VERSION 5.7 ;
  NOWIREEXTENSIONATPIN ON ;
  DIVIDERCHAR "/" ;
  BUSBITCHARS "[]" ;
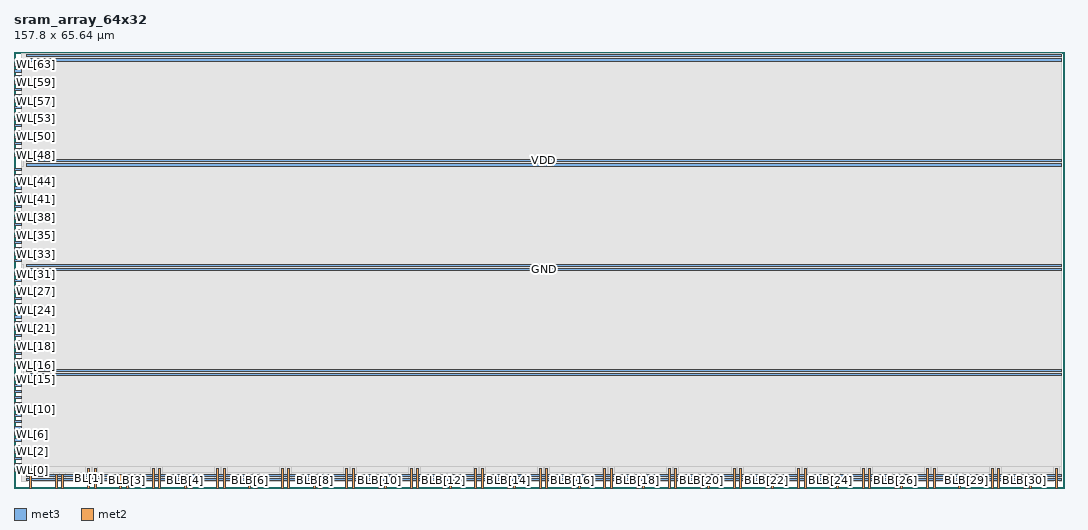
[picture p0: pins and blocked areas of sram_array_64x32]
MACRO sram_array_64x32
  CLASS BLOCK ;
  FOREIGN sram_array_64x32 ;
  ORIGIN 0.000 0.000 ;
  SIZE 157.800 BY 65.640 ;
  PIN WL[0]
    DIRECTION INPUT ;
    USE SIGNAL ;
    ANTENNAGATEAREA 4.032000 ;
    PORT
      LAYER met3 ;
        RECT 0.000 2.490 1.160 2.820 ;
    END
  END WL[0]
  PIN WL[1]
    DIRECTION INPUT ;
    USE SIGNAL ;
    ANTENNAGATEAREA 4.032000 ;
    PORT
      LAYER met3 ;
        RECT 0.000 3.400 1.160 3.730 ;
    END
  END WL[1]
  PIN WL[2]
    DIRECTION INPUT ;
    USE SIGNAL ;
    ANTENNAGATEAREA 4.032000 ;
    PORT
      LAYER met3 ;
        RECT 0.000 4.310 1.160 4.640 ;
    END
  END WL[2]
  PIN WL[3]
    DIRECTION INPUT ;
    USE SIGNAL ;
    ANTENNAGATEAREA 4.032000 ;
    PORT
      LAYER met3 ;
        RECT 0.000 5.220 1.160 5.550 ;
    END
  END WL[3]
  PIN WL[4]
    DIRECTION INPUT ;
    USE SIGNAL ;
    ANTENNAGATEAREA 4.032000 ;
    PORT
      LAYER met3 ;
        RECT 0.000 6.130 1.160 6.460 ;
    END
  END WL[4]
  PIN WL[5]
    DIRECTION INPUT ;
    USE SIGNAL ;
    ANTENNAGATEAREA 4.032000 ;
    PORT
      LAYER met3 ;
        RECT 0.000 7.040 1.160 7.370 ;
    END
  END WL[5]
  PIN WL[6]
    DIRECTION INPUT ;
    USE SIGNAL ;
    ANTENNAGATEAREA 4.032000 ;
    PORT
      LAYER met3 ;
        RECT 0.000 7.950 1.160 8.280 ;
    END
  END WL[6]
  PIN WL[7]
    DIRECTION INPUT ;
    USE SIGNAL ;
    ANTENNAGATEAREA 4.032000 ;
    PORT
      LAYER met3 ;
        RECT 0.000 8.860 1.160 9.190 ;
    END
  END WL[7]
  PIN WL[8]
    DIRECTION INPUT ;
    USE SIGNAL ;
    ANTENNAGATEAREA 4.032000 ;
    PORT
      LAYER met3 ;
        RECT 0.000 9.770 1.160 10.100 ;
    END
  END WL[8]
  PIN WL[9]
    DIRECTION INPUT ;
    USE SIGNAL ;
    ANTENNAGATEAREA 4.032000 ;
    PORT
      LAYER met3 ;
        RECT 0.000 10.680 1.160 11.010 ;
    END
  END WL[9]
  PIN WL[10]
    DIRECTION INPUT ;
    USE SIGNAL ;
    ANTENNAGATEAREA 4.032000 ;
    PORT
      LAYER met3 ;
        RECT 0.000 11.590 1.160 11.920 ;
    END
  END WL[10]
  PIN WL[11]
    DIRECTION INPUT ;
    USE SIGNAL ;
    ANTENNAGATEAREA 4.032000 ;
    PORT
      LAYER met3 ;
        RECT 0.000 12.500 1.160 12.830 ;
    END
  END WL[11]
  PIN WL[12]
    DIRECTION INPUT ;
    USE SIGNAL ;
    ANTENNAGATEAREA 4.032000 ;
    PORT
      LAYER met3 ;
        RECT 0.000 13.410 1.160 13.740 ;
    END
  END WL[12]
  PIN WL[13]
    DIRECTION INPUT ;
    USE SIGNAL ;
    ANTENNAGATEAREA 4.032000 ;
    PORT
      LAYER met3 ;
        RECT 0.000 14.320 1.160 14.650 ;
    END
  END WL[13]
  PIN WL[14]
    DIRECTION INPUT ;
    USE SIGNAL ;
    ANTENNAGATEAREA 4.032000 ;
    PORT
      LAYER met3 ;
        RECT 0.000 15.230 1.160 15.560 ;
    END
  END WL[14]
  PIN WL[15]
    DIRECTION INPUT ;
    USE SIGNAL ;
    ANTENNAGATEAREA 4.032000 ;
    PORT
      LAYER met3 ;
        RECT 0.000 16.140 1.160 16.470 ;
    END
  END WL[15]
  PIN WL[16]
    DIRECTION INPUT ;
    USE SIGNAL ;
    ANTENNAGATEAREA 4.032000 ;
    PORT
      LAYER met3 ;
        RECT 0.000 18.250 1.160 18.580 ;
    END
  END WL[16]
  PIN WL[17]
    DIRECTION INPUT ;
    USE SIGNAL ;
    ANTENNAGATEAREA 4.032000 ;
    PORT
      LAYER met3 ;
        RECT 0.000 19.160 1.160 19.490 ;
    END
  END WL[17]
  PIN WL[18]
    DIRECTION INPUT ;
    USE SIGNAL ;
    ANTENNAGATEAREA 4.032000 ;
    PORT
      LAYER met3 ;
        RECT 0.000 20.070 1.160 20.400 ;
    END
  END WL[18]
  PIN WL[19]
    DIRECTION INPUT ;
    USE SIGNAL ;
    ANTENNAGATEAREA 4.032000 ;
    PORT
      LAYER met3 ;
        RECT 0.000 20.980 1.160 21.310 ;
    END
  END WL[19]
  PIN WL[20]
    DIRECTION INPUT ;
    USE SIGNAL ;
    ANTENNAGATEAREA 4.032000 ;
    PORT
      LAYER met3 ;
        RECT 0.000 21.890 1.160 22.220 ;
    END
  END WL[20]
  PIN WL[21]
    DIRECTION INPUT ;
    USE SIGNAL ;
    ANTENNAGATEAREA 4.032000 ;
    PORT
      LAYER met3 ;
        RECT 0.000 22.800 1.160 23.130 ;
    END
  END WL[21]
  PIN WL[22]
    DIRECTION INPUT ;
    USE SIGNAL ;
    ANTENNAGATEAREA 4.032000 ;
    PORT
      LAYER met3 ;
        RECT 0.000 23.710 1.160 24.040 ;
    END
  END WL[22]
  PIN WL[23]
    DIRECTION INPUT ;
    USE SIGNAL ;
    ANTENNAGATEAREA 4.032000 ;
    PORT
      LAYER met3 ;
        RECT 0.000 24.620 1.160 24.950 ;
    END
  END WL[23]
  PIN WL[24]
    DIRECTION INPUT ;
    USE SIGNAL ;
    ANTENNAGATEAREA 4.032000 ;
    PORT
      LAYER met3 ;
        RECT 0.000 25.530 1.160 25.860 ;
    END
  END WL[24]
  PIN WL[25]
    DIRECTION INPUT ;
    USE SIGNAL ;
    ANTENNAGATEAREA 4.032000 ;
    PORT
      LAYER met3 ;
        RECT 0.000 26.440 1.160 26.770 ;
    END
  END WL[25]
  PIN WL[26]
    DIRECTION INPUT ;
    USE SIGNAL ;
    ANTENNAGATEAREA 4.032000 ;
    PORT
      LAYER met3 ;
        RECT 0.000 27.350 1.160 27.680 ;
    END
  END WL[26]
  PIN WL[27]
    DIRECTION INPUT ;
    USE SIGNAL ;
    ANTENNAGATEAREA 4.032000 ;
    PORT
      LAYER met3 ;
        RECT 0.000 28.260 1.160 28.590 ;
    END
  END WL[27]
  PIN WL[28]
    DIRECTION INPUT ;
    USE SIGNAL ;
    ANTENNAGATEAREA 4.032000 ;
    PORT
      LAYER met3 ;
        RECT 0.000 29.170 1.160 29.500 ;
    END
  END WL[28]
  PIN WL[29]
    DIRECTION INPUT ;
    USE SIGNAL ;
    ANTENNAGATEAREA 4.032000 ;
    PORT
      LAYER met3 ;
        RECT 0.000 30.080 1.160 30.410 ;
    END
  END WL[29]
  PIN WL[30]
    DIRECTION INPUT ;
    USE SIGNAL ;
    ANTENNAGATEAREA 4.032000 ;
    PORT
      LAYER met3 ;
        RECT 0.000 30.990 1.160 31.320 ;
    END
  END WL[30]
  PIN WL[31]
    DIRECTION INPUT ;
    USE SIGNAL ;
    ANTENNAGATEAREA 4.032000 ;
    PORT
      LAYER met3 ;
        RECT 0.000 31.900 1.160 32.230 ;
    END
  END WL[31]
  PIN WL[32]
    DIRECTION INPUT ;
    USE SIGNAL ;
    ANTENNAGATEAREA 4.032000 ;
    PORT
      LAYER met3 ;
        RECT 0.000 34.010 1.160 34.340 ;
    END
  END WL[32]
  PIN WL[33]
    DIRECTION INPUT ;
    USE SIGNAL ;
    ANTENNAGATEAREA 4.032000 ;
    PORT
      LAYER met3 ;
        RECT 0.000 34.920 1.160 35.250 ;
    END
  END WL[33]
  PIN WL[34]
    DIRECTION INPUT ;
    USE SIGNAL ;
    ANTENNAGATEAREA 4.032000 ;
    PORT
      LAYER met3 ;
        RECT 0.000 35.830 1.160 36.160 ;
    END
  END WL[34]
  PIN WL[35]
    DIRECTION INPUT ;
    USE SIGNAL ;
    ANTENNAGATEAREA 4.032000 ;
    PORT
      LAYER met3 ;
        RECT 0.000 36.740 1.160 37.070 ;
    END
  END WL[35]
  PIN WL[36]
    DIRECTION INPUT ;
    USE SIGNAL ;
    ANTENNAGATEAREA 4.032000 ;
    PORT
      LAYER met3 ;
        RECT 0.000 37.650 1.160 37.980 ;
    END
  END WL[36]
  PIN WL[37]
    DIRECTION INPUT ;
    USE SIGNAL ;
    ANTENNAGATEAREA 4.032000 ;
    PORT
      LAYER met3 ;
        RECT 0.000 38.560 1.160 38.890 ;
    END
  END WL[37]
  PIN WL[38]
    DIRECTION INPUT ;
    USE SIGNAL ;
    ANTENNAGATEAREA 4.032000 ;
    PORT
      LAYER met3 ;
        RECT 0.000 39.470 1.160 39.800 ;
    END
  END WL[38]
  PIN WL[39]
    DIRECTION INPUT ;
    USE SIGNAL ;
    ANTENNAGATEAREA 4.032000 ;
    PORT
      LAYER met3 ;
        RECT 0.000 40.380 1.160 40.710 ;
    END
  END WL[39]
  PIN WL[40]
    DIRECTION INPUT ;
    USE SIGNAL ;
    ANTENNAGATEAREA 4.032000 ;
    PORT
      LAYER met3 ;
        RECT 0.000 41.290 1.160 41.620 ;
    END
  END WL[40]
  PIN WL[41]
    DIRECTION INPUT ;
    USE SIGNAL ;
    ANTENNAGATEAREA 4.032000 ;
    PORT
      LAYER met3 ;
        RECT 0.000 42.200 1.160 42.530 ;
    END
  END WL[41]
  PIN WL[42]
    DIRECTION INPUT ;
    USE SIGNAL ;
    ANTENNAGATEAREA 4.032000 ;
    PORT
      LAYER met3 ;
        RECT 0.000 43.110 1.160 43.440 ;
    END
  END WL[42]
  PIN WL[43]
    DIRECTION INPUT ;
    USE SIGNAL ;
    ANTENNAGATEAREA 4.032000 ;
    PORT
      LAYER met3 ;
        RECT 0.000 44.020 1.160 44.350 ;
    END
  END WL[43]
  PIN WL[44]
    DIRECTION INPUT ;
    USE SIGNAL ;
    ANTENNAGATEAREA 4.032000 ;
    PORT
      LAYER met3 ;
        RECT 0.000 44.930 1.160 45.260 ;
    END
  END WL[44]
  PIN WL[45]
    DIRECTION INPUT ;
    USE SIGNAL ;
    ANTENNAGATEAREA 4.032000 ;
    PORT
      LAYER met3 ;
        RECT 0.000 45.840 1.160 46.170 ;
    END
  END WL[45]
  PIN WL[46]
    DIRECTION INPUT ;
    USE SIGNAL ;
    ANTENNAGATEAREA 4.032000 ;
    PORT
      LAYER met3 ;
        RECT 0.000 46.750 1.160 47.080 ;
    END
  END WL[46]
  PIN WL[47]
    DIRECTION INPUT ;
    USE SIGNAL ;
    ANTENNAGATEAREA 4.032000 ;
    PORT
      LAYER met3 ;
        RECT 0.000 47.660 1.160 47.990 ;
    END
  END WL[47]
  PIN WL[48]
    DIRECTION INPUT ;
    USE SIGNAL ;
    ANTENNAGATEAREA 4.032000 ;
    PORT
      LAYER met3 ;
        RECT 0.000 49.770 1.160 50.100 ;
    END
  END WL[48]
  PIN WL[49]
    DIRECTION INPUT ;
    USE SIGNAL ;
    ANTENNAGATEAREA 4.032000 ;
    PORT
      LAYER met3 ;
        RECT 0.000 50.680 1.160 51.010 ;
    END
  END WL[49]
  PIN WL[50]
    DIRECTION INPUT ;
    USE SIGNAL ;
    ANTENNAGATEAREA 4.032000 ;
    PORT
      LAYER met3 ;
        RECT 0.000 51.590 1.160 51.920 ;
    END
  END WL[50]
  PIN WL[51]
    DIRECTION INPUT ;
    USE SIGNAL ;
    ANTENNAGATEAREA 4.032000 ;
    PORT
      LAYER met3 ;
        RECT 0.000 52.500 1.160 52.830 ;
    END
  END WL[51]
  PIN WL[52]
    DIRECTION INPUT ;
    USE SIGNAL ;
    ANTENNAGATEAREA 4.032000 ;
    PORT
      LAYER met3 ;
        RECT 0.000 53.410 1.160 53.740 ;
    END
  END WL[52]
  PIN WL[53]
    DIRECTION INPUT ;
    USE SIGNAL ;
    ANTENNAGATEAREA 4.032000 ;
    PORT
      LAYER met3 ;
        RECT 0.000 54.320 1.160 54.650 ;
    END
  END WL[53]
  PIN WL[54]
    DIRECTION INPUT ;
    USE SIGNAL ;
    ANTENNAGATEAREA 4.032000 ;
    PORT
      LAYER met3 ;
        RECT 0.000 55.230 1.160 55.560 ;
    END
  END WL[54]
  PIN WL[55]
    DIRECTION INPUT ;
    USE SIGNAL ;
    ANTENNAGATEAREA 4.032000 ;
    PORT
      LAYER met3 ;
        RECT 0.000 56.140 1.160 56.470 ;
    END
  END WL[55]
  PIN WL[56]
    DIRECTION INPUT ;
    USE SIGNAL ;
    ANTENNAGATEAREA 4.032000 ;
    PORT
      LAYER met3 ;
        RECT 0.000 57.050 1.160 57.380 ;
    END
  END WL[56]
  PIN WL[57]
    DIRECTION INPUT ;
    USE SIGNAL ;
    ANTENNAGATEAREA 4.032000 ;
    PORT
      LAYER met3 ;
        RECT 0.000 57.960 1.160 58.290 ;
    END
  END WL[57]
  PIN WL[58]
    DIRECTION INPUT ;
    USE SIGNAL ;
    ANTENNAGATEAREA 4.032000 ;
    PORT
      LAYER met3 ;
        RECT 0.000 58.870 1.160 59.200 ;
    END
  END WL[58]
  PIN WL[59]
    DIRECTION INPUT ;
    USE SIGNAL ;
    ANTENNAGATEAREA 4.032000 ;
    PORT
      LAYER met3 ;
        RECT 0.000 59.780 1.160 60.110 ;
    END
  END WL[59]
  PIN WL[60]
    DIRECTION INPUT ;
    USE SIGNAL ;
    ANTENNAGATEAREA 4.032000 ;
    PORT
      LAYER met3 ;
        RECT 0.000 60.690 1.160 61.020 ;
    END
  END WL[60]
  PIN WL[61]
    DIRECTION INPUT ;
    USE SIGNAL ;
    ANTENNAGATEAREA 4.032000 ;
    PORT
      LAYER met3 ;
        RECT 0.000 61.600 1.160 61.930 ;
    END
  END WL[61]
  PIN WL[62]
    DIRECTION INPUT ;
    USE SIGNAL ;
    ANTENNAGATEAREA 4.032000 ;
    PORT
      LAYER met3 ;
        RECT 0.000 62.510 1.160 62.840 ;
    END
  END WL[62]
  PIN WL[63]
    DIRECTION INPUT ;
    USE SIGNAL ;
    ANTENNAGATEAREA 4.032000 ;
    PORT
      LAYER met3 ;
        RECT 0.000 63.420 1.160 63.750 ;
    END
  END WL[63]
  PIN BL[0]
    DIRECTION INOUT ;
    USE SIGNAL ;
    ANTENNADIFFAREA 3.763200 ;
    PORT
      LAYER met2 ;
        RECT 2.335 0.000 2.635 2.980 ;
    END
  END BL[0]
  PIN BLB[0]
    DIRECTION INOUT ;
    USE SIGNAL ;
    ANTENNADIFFAREA 4.233600 ;
    PORT
      LAYER met2 ;
        RECT 6.215 0.000 6.515 2.070 ;
    END
  END BLB[0]
  PIN BL[1]
    DIRECTION INOUT ;
    USE SIGNAL ;
    ANTENNADIFFAREA 3.763200 ;
    PORT
      LAYER met2 ;
        RECT 11.065 0.000 11.365 2.980 ;
    END
  END BL[1]
  PIN BLB[1]
    DIRECTION INOUT ;
    USE SIGNAL ;
    ANTENNADIFFAREA 4.233600 ;
    PORT
      LAYER met2 ;
        RECT 7.185 0.000 7.485 2.070 ;
    END
  END BLB[1]
  PIN BL[2]
    DIRECTION INOUT ;
    USE SIGNAL ;
    ANTENNADIFFAREA 3.763200 ;
    PORT
      LAYER met2 ;
        RECT 12.035 0.000 12.335 2.980 ;
    END
  END BL[2]
  PIN BLB[2]
    DIRECTION INOUT ;
    USE SIGNAL ;
    ANTENNADIFFAREA 4.233600 ;
    PORT
      LAYER met2 ;
        RECT 15.915 0.000 16.215 2.070 ;
    END
  END BLB[2]
  PIN BL[3]
    DIRECTION INOUT ;
    USE SIGNAL ;
    ANTENNADIFFAREA 3.763200 ;
    PORT
      LAYER met2 ;
        RECT 20.765 0.000 21.065 2.980 ;
    END
  END BL[3]
  PIN BLB[3]
    DIRECTION INOUT ;
    USE SIGNAL ;
    ANTENNADIFFAREA 4.233600 ;
    PORT
      LAYER met2 ;
        RECT 16.885 0.000 17.185 2.070 ;
    END
  END BLB[3]
  PIN BL[4]
    DIRECTION INOUT ;
    USE SIGNAL ;
    ANTENNADIFFAREA 3.763200 ;
    PORT
      LAYER met2 ;
        RECT 21.735 0.000 22.035 2.980 ;
    END
  END BL[4]
  PIN BLB[4]
    DIRECTION INOUT ;
    USE SIGNAL ;
    ANTENNADIFFAREA 4.233600 ;
    PORT
      LAYER met2 ;
        RECT 25.615 0.000 25.915 2.070 ;
    END
  END BLB[4]
  PIN BL[5]
    DIRECTION INOUT ;
    USE SIGNAL ;
    ANTENNADIFFAREA 3.763200 ;
    PORT
      LAYER met2 ;
        RECT 30.465 0.000 30.765 2.980 ;
    END
  END BL[5]
  PIN BLB[5]
    DIRECTION INOUT ;
    USE SIGNAL ;
    ANTENNADIFFAREA 4.233600 ;
    PORT
      LAYER met2 ;
        RECT 26.585 0.000 26.885 2.070 ;
    END
  END BLB[5]
  PIN BL[6]
    DIRECTION INOUT ;
    USE SIGNAL ;
    ANTENNADIFFAREA 3.763200 ;
    PORT
      LAYER met2 ;
        RECT 31.435 0.000 31.735 2.980 ;
    END
  END BL[6]
  PIN BLB[6]
    DIRECTION INOUT ;
    USE SIGNAL ;
    ANTENNADIFFAREA 4.233600 ;
    PORT
      LAYER met2 ;
        RECT 35.315 0.000 35.615 2.070 ;
    END
  END BLB[6]
  PIN BL[7]
    DIRECTION INOUT ;
    USE SIGNAL ;
    ANTENNADIFFAREA 3.763200 ;
    PORT
      LAYER met2 ;
        RECT 40.165 0.000 40.465 2.980 ;
    END
  END BL[7]
  PIN BLB[7]
    DIRECTION INOUT ;
    USE SIGNAL ;
    ANTENNADIFFAREA 4.233600 ;
    PORT
      LAYER met2 ;
        RECT 36.285 0.000 36.585 2.070 ;
    END
  END BLB[7]
  PIN BL[8]
    DIRECTION INOUT ;
    USE SIGNAL ;
    ANTENNADIFFAREA 3.763200 ;
    PORT
      LAYER met2 ;
        RECT 41.135 0.000 41.435 2.980 ;
    END
  END BL[8]
  PIN BLB[8]
    DIRECTION INOUT ;
    USE SIGNAL ;
    ANTENNADIFFAREA 4.233600 ;
    PORT
      LAYER met2 ;
        RECT 45.015 0.000 45.315 2.070 ;
    END
  END BLB[8]
  PIN BL[9]
    DIRECTION INOUT ;
    USE SIGNAL ;
    ANTENNADIFFAREA 3.763200 ;
    PORT
      LAYER met2 ;
        RECT 49.865 0.000 50.165 2.980 ;
    END
  END BL[9]
  PIN BLB[9]
    DIRECTION INOUT ;
    USE SIGNAL ;
    ANTENNADIFFAREA 4.233600 ;
    PORT
      LAYER met2 ;
        RECT 45.985 0.000 46.285 2.070 ;
    END
  END BLB[9]
  PIN BL[10]
    DIRECTION INOUT ;
    USE SIGNAL ;
    ANTENNADIFFAREA 3.763200 ;
    PORT
      LAYER met2 ;
        RECT 50.835 0.000 51.135 2.980 ;
    END
  END BL[10]
  PIN BLB[10]
    DIRECTION INOUT ;
    USE SIGNAL ;
    ANTENNADIFFAREA 4.233600 ;
    PORT
      LAYER met2 ;
        RECT 54.715 0.000 55.015 2.070 ;
    END
  END BLB[10]
  PIN BL[11]
    DIRECTION INOUT ;
    USE SIGNAL ;
    ANTENNADIFFAREA 3.763200 ;
    PORT
      LAYER met2 ;
        RECT 59.565 0.000 59.865 2.980 ;
    END
  END BL[11]
  PIN BLB[11]
    DIRECTION INOUT ;
    USE SIGNAL ;
    ANTENNADIFFAREA 4.233600 ;
    PORT
      LAYER met2 ;
        RECT 55.685 0.000 55.985 2.070 ;
    END
  END BLB[11]
  PIN BL[12]
    DIRECTION INOUT ;
    USE SIGNAL ;
    ANTENNADIFFAREA 3.763200 ;
    PORT
      LAYER met2 ;
        RECT 60.535 0.000 60.835 2.980 ;
    END
  END BL[12]
  PIN BLB[12]
    DIRECTION INOUT ;
    USE SIGNAL ;
    ANTENNADIFFAREA 4.233600 ;
    PORT
      LAYER met2 ;
        RECT 64.415 0.000 64.715 2.070 ;
    END
  END BLB[12]
  PIN BL[13]
    DIRECTION INOUT ;
    USE SIGNAL ;
    ANTENNADIFFAREA 3.763200 ;
    PORT
      LAYER met2 ;
        RECT 69.265 0.000 69.565 2.980 ;
    END
  END BL[13]
  PIN BLB[13]
    DIRECTION INOUT ;
    USE SIGNAL ;
    ANTENNADIFFAREA 4.233600 ;
    PORT
      LAYER met2 ;
        RECT 65.385 0.000 65.685 2.070 ;
    END
  END BLB[13]
  PIN BL[14]
    DIRECTION INOUT ;
    USE SIGNAL ;
    ANTENNADIFFAREA 3.763200 ;
    PORT
      LAYER met2 ;
        RECT 70.235 0.000 70.535 2.980 ;
    END
  END BL[14]
  PIN BLB[14]
    DIRECTION INOUT ;
    USE SIGNAL ;
    ANTENNADIFFAREA 4.233600 ;
    PORT
      LAYER met2 ;
        RECT 74.115 0.000 74.415 2.070 ;
    END
  END BLB[14]
  PIN BL[15]
    DIRECTION INOUT ;
    USE SIGNAL ;
    ANTENNADIFFAREA 3.763200 ;
    PORT
      LAYER met2 ;
        RECT 78.965 0.000 79.265 2.980 ;
    END
  END BL[15]
  PIN BLB[15]
    DIRECTION INOUT ;
    USE SIGNAL ;
    ANTENNADIFFAREA 4.233600 ;
    PORT
      LAYER met2 ;
        RECT 75.085 0.000 75.385 2.070 ;
    END
  END BLB[15]
  PIN BL[16]
    DIRECTION INOUT ;
    USE SIGNAL ;
    ANTENNADIFFAREA 3.763200 ;
    PORT
      LAYER met2 ;
        RECT 79.935 0.000 80.235 2.980 ;
    END
  END BL[16]
  PIN BLB[16]
    DIRECTION INOUT ;
    USE SIGNAL ;
    ANTENNADIFFAREA 4.233600 ;
    PORT
      LAYER met2 ;
        RECT 83.815 0.000 84.115 2.070 ;
    END
  END BLB[16]
  PIN BL[17]
    DIRECTION INOUT ;
    USE SIGNAL ;
    ANTENNADIFFAREA 3.763200 ;
    PORT
      LAYER met2 ;
        RECT 88.665 0.000 88.965 2.980 ;
    END
  END BL[17]
  PIN BLB[17]
    DIRECTION INOUT ;
    USE SIGNAL ;
    ANTENNADIFFAREA 4.233600 ;
    PORT
      LAYER met2 ;
        RECT 84.785 0.000 85.085 2.070 ;
    END
  END BLB[17]
  PIN BL[18]
    DIRECTION INOUT ;
    USE SIGNAL ;
    ANTENNADIFFAREA 3.763200 ;
    PORT
      LAYER met2 ;
        RECT 89.635 0.000 89.935 2.980 ;
    END
  END BL[18]
  PIN BLB[18]
    DIRECTION INOUT ;
    USE SIGNAL ;
    ANTENNADIFFAREA 4.233600 ;
    PORT
      LAYER met2 ;
        RECT 93.515 0.000 93.815 2.070 ;
    END
  END BLB[18]
  PIN BL[19]
    DIRECTION INOUT ;
    USE SIGNAL ;
    ANTENNADIFFAREA 3.763200 ;
    PORT
      LAYER met2 ;
        RECT 98.365 0.000 98.665 2.980 ;
    END
  END BL[19]
  PIN BLB[19]
    DIRECTION INOUT ;
    USE SIGNAL ;
    ANTENNADIFFAREA 4.233600 ;
    PORT
      LAYER met2 ;
        RECT 94.485 0.000 94.785 2.070 ;
    END
  END BLB[19]
  PIN BL[20]
    DIRECTION INOUT ;
    USE SIGNAL ;
    ANTENNADIFFAREA 3.763200 ;
    PORT
      LAYER met2 ;
        RECT 99.335 0.000 99.635 2.980 ;
    END
  END BL[20]
  PIN BLB[20]
    DIRECTION INOUT ;
    USE SIGNAL ;
    ANTENNADIFFAREA 4.233600 ;
    PORT
      LAYER met2 ;
        RECT 103.215 0.000 103.515 2.070 ;
    END
  END BLB[20]
  PIN BL[21]
    DIRECTION INOUT ;
    USE SIGNAL ;
    ANTENNADIFFAREA 3.763200 ;
    PORT
      LAYER met2 ;
        RECT 108.065 0.000 108.365 2.980 ;
    END
  END BL[21]
  PIN BLB[21]
    DIRECTION INOUT ;
    USE SIGNAL ;
    ANTENNADIFFAREA 4.233600 ;
    PORT
      LAYER met2 ;
        RECT 104.185 0.000 104.485 2.070 ;
    END
  END BLB[21]
  PIN BL[22]
    DIRECTION INOUT ;
    USE SIGNAL ;
    ANTENNADIFFAREA 3.763200 ;
    PORT
      LAYER met2 ;
        RECT 109.035 0.000 109.335 2.980 ;
    END
  END BL[22]
  PIN BLB[22]
    DIRECTION INOUT ;
    USE SIGNAL ;
    ANTENNADIFFAREA 4.233600 ;
    PORT
      LAYER met2 ;
        RECT 112.915 0.000 113.215 2.070 ;
    END
  END BLB[22]
  PIN BL[23]
    DIRECTION INOUT ;
    USE SIGNAL ;
    ANTENNADIFFAREA 3.763200 ;
    PORT
      LAYER met2 ;
        RECT 117.765 0.000 118.065 2.980 ;
    END
  END BL[23]
  PIN BLB[23]
    DIRECTION INOUT ;
    USE SIGNAL ;
    ANTENNADIFFAREA 4.233600 ;
    PORT
      LAYER met2 ;
        RECT 113.885 0.000 114.185 2.070 ;
    END
  END BLB[23]
  PIN BL[24]
    DIRECTION INOUT ;
    USE SIGNAL ;
    ANTENNADIFFAREA 3.763200 ;
    PORT
      LAYER met2 ;
        RECT 118.735 0.000 119.035 2.980 ;
    END
  END BL[24]
  PIN BLB[24]
    DIRECTION INOUT ;
    USE SIGNAL ;
    ANTENNADIFFAREA 4.233600 ;
    PORT
      LAYER met2 ;
        RECT 122.615 0.000 122.915 2.070 ;
    END
  END BLB[24]
  PIN BL[25]
    DIRECTION INOUT ;
    USE SIGNAL ;
    ANTENNADIFFAREA 3.763200 ;
    PORT
      LAYER met2 ;
        RECT 127.465 0.000 127.765 2.980 ;
    END
  END BL[25]
  PIN BLB[25]
    DIRECTION INOUT ;
    USE SIGNAL ;
    ANTENNADIFFAREA 4.233600 ;
    PORT
      LAYER met2 ;
        RECT 123.585 0.000 123.885 2.070 ;
    END
  END BLB[25]
  PIN BL[26]
    DIRECTION INOUT ;
    USE SIGNAL ;
    ANTENNADIFFAREA 3.763200 ;
    PORT
      LAYER met2 ;
        RECT 128.435 0.000 128.735 2.980 ;
    END
  END BL[26]
  PIN BLB[26]
    DIRECTION INOUT ;
    USE SIGNAL ;
    ANTENNADIFFAREA 4.233600 ;
    PORT
      LAYER met2 ;
        RECT 132.315 0.000 132.615 2.070 ;
    END
  END BLB[26]
  PIN BL[27]
    DIRECTION INOUT ;
    USE SIGNAL ;
    ANTENNADIFFAREA 3.763200 ;
    PORT
      LAYER met2 ;
        RECT 137.165 0.000 137.465 2.980 ;
    END
  END BL[27]
  PIN BLB[27]
    DIRECTION INOUT ;
    USE SIGNAL ;
    ANTENNADIFFAREA 4.233600 ;
    PORT
      LAYER met2 ;
        RECT 133.285 0.000 133.585 2.070 ;
    END
  END BLB[27]
  PIN BL[28]
    DIRECTION INOUT ;
    USE SIGNAL ;
    ANTENNADIFFAREA 3.763200 ;
    PORT
      LAYER met2 ;
        RECT 138.135 0.000 138.435 2.980 ;
    END
  END BL[28]
  PIN BLB[28]
    DIRECTION INOUT ;
    USE SIGNAL ;
    ANTENNADIFFAREA 4.233600 ;
    PORT
      LAYER met2 ;
        RECT 142.015 0.000 142.315 2.070 ;
    END
  END BLB[28]
  PIN BL[29]
    DIRECTION INOUT ;
    USE SIGNAL ;
    ANTENNADIFFAREA 3.763200 ;
    PORT
      LAYER met2 ;
        RECT 146.865 0.000 147.165 2.980 ;
    END
  END BL[29]
  PIN BLB[29]
    DIRECTION INOUT ;
    USE SIGNAL ;
    ANTENNADIFFAREA 4.233600 ;
    PORT
      LAYER met2 ;
        RECT 142.985 0.000 143.285 2.070 ;
    END
  END BLB[29]
  PIN BL[30]
    DIRECTION INOUT ;
    USE SIGNAL ;
    ANTENNADIFFAREA 3.763200 ;
    PORT
      LAYER met2 ;
        RECT 147.835 0.000 148.135 2.980 ;
    END
  END BL[30]
  PIN BLB[30]
    DIRECTION INOUT ;
    USE SIGNAL ;
    ANTENNADIFFAREA 4.233600 ;
    PORT
      LAYER met2 ;
        RECT 151.715 0.000 152.015 2.070 ;
    END
  END BLB[30]
  PIN BL[31]
    DIRECTION INOUT ;
    USE SIGNAL ;
    ANTENNADIFFAREA 3.763200 ;
    PORT
      LAYER met2 ;
        RECT 156.565 0.000 156.865 2.980 ;
    END
  END BL[31]
  PIN BLB[31]
    DIRECTION INOUT ;
    USE SIGNAL ;
    ANTENNADIFFAREA 4.233600 ;
    PORT
      LAYER met2 ;
        RECT 152.685 0.000 152.985 2.070 ;
    END
  END BLB[31]
  PIN GND
    DIRECTION INOUT ;
    USE GROUND ;
    PORT
      LAYER met3 ;
        RECT 1.835 1.100 157.365 1.440 ;
    END
    PORT
      LAYER met3 ;
        RECT 1.835 16.860 157.365 17.200 ;
    END
    PORT
      LAYER met3 ;
        RECT 1.835 32.620 157.365 32.960 ;
    END
    PORT
      LAYER met3 ;
        RECT 1.835 48.380 157.365 48.720 ;
    END
    PORT
      LAYER met3 ;
        RECT 1.835 64.140 157.365 64.480 ;
    END
  END GND
  PIN VDD
    DIRECTION INOUT ;
    USE POWER ;
    PORT
      LAYER met3 ;
        RECT 1.835 1.760 157.365 2.100 ;
    END
    PORT
      LAYER met3 ;
        RECT 1.835 17.520 157.365 17.860 ;
    END
    PORT
      LAYER met3 ;
        RECT 1.835 33.280 157.365 33.620 ;
    END
    PORT
      LAYER met3 ;
        RECT 1.835 49.040 157.365 49.380 ;
    END
    PORT
      LAYER met3 ;
        RECT 1.835 64.800 157.365 65.140 ;
    END
  END VDD
  OBS
      LAYER nwell ;
        RECT 3.265 1.000 155.935 65.240 ;
      LAYER li1 ;
        RECT 1.835 1.515 157.365 64.725 ;
      LAYER met1 ;
        RECT 1.140 1.440 157.330 64.800 ;
      LAYER met2 ;
        RECT 1.160 3.260 157.350 65.240 ;
        RECT 1.160 1.000 2.055 3.260 ;
        RECT 2.915 2.350 10.785 3.260 ;
        RECT 2.915 1.000 5.935 2.350 ;
        RECT 6.795 1.000 6.905 2.350 ;
        RECT 7.765 1.000 10.785 2.350 ;
        RECT 11.645 1.000 11.755 3.260 ;
        RECT 12.615 2.350 20.485 3.260 ;
        RECT 12.615 1.000 15.635 2.350 ;
        RECT 16.495 1.000 16.605 2.350 ;
        RECT 17.465 1.000 20.485 2.350 ;
        RECT 21.345 1.000 21.455 3.260 ;
        RECT 22.315 2.350 30.185 3.260 ;
        RECT 22.315 1.000 25.335 2.350 ;
        RECT 26.195 1.000 26.305 2.350 ;
        RECT 27.165 1.000 30.185 2.350 ;
        RECT 31.045 1.000 31.155 3.260 ;
        RECT 32.015 2.350 39.885 3.260 ;
        RECT 32.015 1.000 35.035 2.350 ;
        RECT 35.895 1.000 36.005 2.350 ;
        RECT 36.865 1.000 39.885 2.350 ;
        RECT 40.745 1.000 40.855 3.260 ;
        RECT 41.715 2.350 49.585 3.260 ;
        RECT 41.715 1.000 44.735 2.350 ;
        RECT 45.595 1.000 45.705 2.350 ;
        RECT 46.565 1.000 49.585 2.350 ;
        RECT 50.445 1.000 50.555 3.260 ;
        RECT 51.415 2.350 59.285 3.260 ;
        RECT 51.415 1.000 54.435 2.350 ;
        RECT 55.295 1.000 55.405 2.350 ;
        RECT 56.265 1.000 59.285 2.350 ;
        RECT 60.145 1.000 60.255 3.260 ;
        RECT 61.115 2.350 68.985 3.260 ;
        RECT 61.115 1.000 64.135 2.350 ;
        RECT 64.995 1.000 65.105 2.350 ;
        RECT 65.965 1.000 68.985 2.350 ;
        RECT 69.845 1.000 69.955 3.260 ;
        RECT 70.815 2.350 78.685 3.260 ;
        RECT 70.815 1.000 73.835 2.350 ;
        RECT 74.695 1.000 74.805 2.350 ;
        RECT 75.665 1.000 78.685 2.350 ;
        RECT 79.545 1.000 79.655 3.260 ;
        RECT 80.515 2.350 88.385 3.260 ;
        RECT 80.515 1.000 83.535 2.350 ;
        RECT 84.395 1.000 84.505 2.350 ;
        RECT 85.365 1.000 88.385 2.350 ;
        RECT 89.245 1.000 89.355 3.260 ;
        RECT 90.215 2.350 98.085 3.260 ;
        RECT 90.215 1.000 93.235 2.350 ;
        RECT 94.095 1.000 94.205 2.350 ;
        RECT 95.065 1.000 98.085 2.350 ;
        RECT 98.945 1.000 99.055 3.260 ;
        RECT 99.915 2.350 107.785 3.260 ;
        RECT 99.915 1.000 102.935 2.350 ;
        RECT 103.795 1.000 103.905 2.350 ;
        RECT 104.765 1.000 107.785 2.350 ;
        RECT 108.645 1.000 108.755 3.260 ;
        RECT 109.615 2.350 117.485 3.260 ;
        RECT 109.615 1.000 112.635 2.350 ;
        RECT 113.495 1.000 113.605 2.350 ;
        RECT 114.465 1.000 117.485 2.350 ;
        RECT 118.345 1.000 118.455 3.260 ;
        RECT 119.315 2.350 127.185 3.260 ;
        RECT 119.315 1.000 122.335 2.350 ;
        RECT 123.195 1.000 123.305 2.350 ;
        RECT 124.165 1.000 127.185 2.350 ;
        RECT 128.045 1.000 128.155 3.260 ;
        RECT 129.015 2.350 136.885 3.260 ;
        RECT 129.015 1.000 132.035 2.350 ;
        RECT 132.895 1.000 133.005 2.350 ;
        RECT 133.865 1.000 136.885 2.350 ;
        RECT 137.745 1.000 137.855 3.260 ;
        RECT 138.715 2.350 146.585 3.260 ;
        RECT 138.715 1.000 141.735 2.350 ;
        RECT 142.595 1.000 142.705 2.350 ;
        RECT 143.565 1.000 146.585 2.350 ;
        RECT 147.445 1.000 147.555 3.260 ;
        RECT 148.415 2.350 156.285 3.260 ;
        RECT 148.415 1.000 151.435 2.350 ;
        RECT 152.295 1.000 152.405 2.350 ;
        RECT 153.265 1.000 156.285 2.350 ;
        RECT 157.145 1.000 157.350 3.260 ;
      LAYER met3 ;
        RECT 1.160 48.390 1.435 49.370 ;
        RECT 1.160 32.630 1.435 33.610 ;
        RECT 1.160 16.870 1.435 17.850 ;
  END
END sram_array_64x32
END LIBRARY

